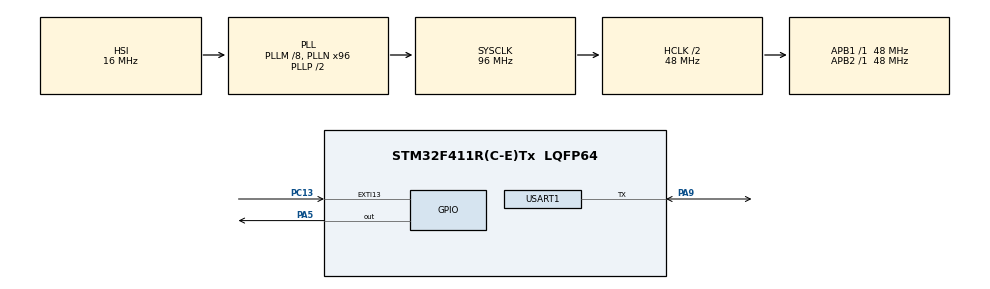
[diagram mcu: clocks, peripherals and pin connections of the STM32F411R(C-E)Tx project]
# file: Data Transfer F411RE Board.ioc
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Dma.Request0=USART1_RX
Dma.Request1=USART1_TX
Dma.USART1_RX.0.Direction=DMA_PERIPH_TO_MEMORY
Dma.USART1_RX.0.FIFOMode=DMA_FIFOMODE_DISABLE
Dma.USART1_RX.0.Instance=DMA2_Stream2
Dma.USART1_RX.0.MemDataAlignment=DMA_MDATAALIGN_BYTE
Dma.USART1_RX.0.MemInc=DMA_MINC_ENABLE
Dma.USART1_RX.0.Mode=DMA_NORMAL
Dma.USART1_RX.0.PeriphDataAlignment=DMA_PDATAALIGN_BYTE
Dma.USART1_RX.0.PeriphInc=DMA_PINC_DISABLE
Dma.USART1_RX.0.Priority=DMA_PRIORITY_LOW
Dma.USART1_TX.1.Direction=DMA_MEMORY_TO_PERIPH
Dma.USART1_TX.1.FIFOMode=DMA_FIFOMODE_DISABLE
Dma.USART1_TX.1.Instance=DMA2_Stream7
Dma.USART1_TX.1.MemDataAlignment=DMA_MDATAALIGN_BYTE
Dma.USART1_TX.1.MemInc=DMA_MINC_ENABLE
Dma.USART1_TX.1.Mode=DMA_NORMAL
Dma.USART1_TX.1.PeriphDataAlignment=DMA_PDATAALIGN_BYTE
Dma.USART1_TX.1.PeriphInc=DMA_PINC_DISABLE
Dma.USART1_TX.1.Priority=DMA_PRIORITY_LOW
Mcu.Family=STM32F4
Mcu.Name=STM32F411R(C-E)Tx
Mcu.Package=LQFP64
NVIC.DMA2_Stream2_IRQn=true\:0\:0\:false\:false\:true\:false\:true\:true
NVIC.DMA2_Stream7_IRQn=true\:0\:0\:false\:false\:true\:false\:true\:true
NVIC.EXTI15_10_IRQn=true\:0\:0\:false\:false\:true\:true\:true\:true
NVIC.PriorityGroup=NVIC_PRIORITYGROUP_0
NVIC.USART1_IRQn=true\:0\:0\:false\:false\:true\:true\:true\:true
PA13.GPIO_Label=TMS
PA13.Mode=Trace_Asynchronous_SW
PA13.Signal=SYS_JTMS-SWDIO
PA14.GPIO_Label=TCK
PA14.Mode=Trace_Asynchronous_SW
PA14.Signal=SYS_JTCK-SWCLK
PA2.GPIO_Label=USART_TX
PA2.Signal=USART2_TX
PA3.GPIO_Label=USART_RX
PA3.Signal=USART2_RX
PA5.Signal=GPIO_Output
PA9.GPIO_PuPd=GPIO_PULLUP
PA9.Mode=Half_duplex(single_wire_mode)
PA9.Signal=USART1_TX
PB3.GPIO_Label=SWO
PB3.Mode=Trace_Asynchronous_SW
PB3.Signal=SYS_JTDO-SWO
PC13-ANTI_TAMP.GPIO_PuPd=GPIO_PULLUP
PC13-ANTI_TAMP.Signal=GPXTI13
PC14-OSC32_IN.Mode=LSE-External-Oscillator
PC14-OSC32_IN.Signal=RCC_OSC32_IN
PC15-OSC32_OUT.Mode=LSE-External-Oscillator
PC15-OSC32_OUT.Signal=RCC_OSC32_OUT
PH0\ -\ OSC_IN.Mode=HSE-External-Clock-Source
PH0\ -\ OSC_IN.Signal=RCC_OSC_IN
PH1\ -\ OSC_OUT.Mode=HSE-External-Clock-Source
PH1\ -\ OSC_OUT.Signal=RCC_OSC_OUT
ProjectManager.HeapSize=0x200
ProjectManager.StackSize=0x400
ProjectManager.TargetToolchain=STM32CubeIDE
RCC.48MHZClocksFreq_Value=48000000
RCC.AHBCLKDivider=RCC_SYSCLK_DIV2
RCC.AHBFreq_Value=48000000
RCC.APB1Freq_Value=48000000
RCC.APB1TimFreq_Value=48000000
RCC.APB2Freq_Value=48000000
RCC.APB2TimFreq_Value=48000000
RCC.CortexFreq_Value=48000000
RCC.FLatency-AdvancedSettings=FLASH_LATENCY_1
RCC.HCLKFreq_Value=48000000
RCC.HSE_VALUE=8000000
RCC.HSI_VALUE=16000000
RCC.PLLM=8
RCC.PLLN=96
RCC.SYSCLKFreq_VALUE=96000000
RCC.SYSCLKSource=RCC_SYSCLKSOURCE_PLLCLK
RCC.VCOOutputFreq_Value=192000000
USART1.BaudRate=9600
USART1.VirtualMode=VM_ASYNC
board=NUCLEO-F411RE

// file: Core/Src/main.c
#include "main.h"
#include "stdio.h"

UART_HandleTypeDef huart1;
DMA_HandleTypeDef hdma_usart1_rx;
DMA_HandleTypeDef hdma_usart1_tx;

void SystemClock_Config(void);
static void MX_GPIO_Init(void);
static void MX_DMA_Init(void);
static void MX_USART1_UART_Init(void);
void DisplayValue(uint8_t value);

//bit0=A, bit1=B, bit2=C, bit3=D, bit4=E, bit5=F, bit6=G
const uint8_t SegmentMap[16] = {
	0b00111111, // 0
	0b00000110, // 1
	0b01011011, // 2
	0b01001111, // 3
	0b01100110, // 4
	0b01101101, // 5
	0b01111101, // 6
	0b00000111, // 7
	0b01111111, // 8
	0b01101111, // 9
	0b01110111, // A
	0b01111100, // B
	0b00111001, // C
	0b01011110, // D
	0b01111001, // E
	0b01110001  // F
};

typedef enum {
    STATE_IDLE,
    STATE_SEND_UART,
	STATE_PROCESS_RX
} SystemState_t;

SystemState_t currentState = STATE_IDLE;

uint8_t RxData[1];
uint8_t TxData[1];
uint8_t receivedValue = 0;
uint8_t rxFlag = 0;
uint8_t count = 0;
uint8_t isClicked = 0;

void HAL_UARTEx_RxEventCallback(UART_HandleTypeDef *huart, uint16_t Size)
{
	if (huart->Instance == USART1)
	{
		receivedValue = RxData[0];
		rxFlag = 1;

		HAL_UARTEx_ReceiveToIdle_IT(&huart1, RxData, 1);
	    }
}

void HAL_GPIO_EXTI_Callback(uint16_t GPIO_Pin)
{
	if (GPIO_Pin == GPIO_PIN_13)
	{
		isClicked = 1;
	}
}

int main(void)
{
  HAL_Init();
  SystemClock_Config();
  MX_GPIO_Init();
  MX_DMA_Init();
  MX_USART1_UART_Init();

  HAL_HalfDuplex_EnableReceiver(&huart1);
  HAL_UARTEx_ReceiveToIdle_IT(&huart1, RxData, 1);

  DisplayValue(count);

  while (1)
  {
  switch (currentState)
  {
	  case STATE_IDLE:
		  if (isClicked)
		  {
			  currentState = STATE_SEND_UART;
		  } else if (rxFlag)
		  {
			  currentState = STATE_PROCESS_RX;
		  }
		  break;

	  case STATE_SEND_UART:
	  {
		  HAL_Delay(100); // debounce
		  TxData[0] = count;

		  HAL_HalfDuplex_EnableTransmitter(&huart1);
		  HAL_UART_Transmit(&huart1, TxData, 1, 1000);
		  HAL_HalfDuplex_EnableReceiver(&huart1);

		  isClicked = 0;
		  currentState = STATE_IDLE;
		  break;
	  }

	  case STATE_PROCESS_RX:
	          {
	              count = receivedValue + 1;
	              if (count > 15)
	              {
	            	  count = 0;
	              }
	              DisplayValue(count);
	              rxFlag = 0;

	              currentState = STATE_IDLE;
	              break;
	          }

	  default:
		  currentState = STATE_IDLE;
		  break;
       }
   }
}

void DisplayValue(uint8_t value)
{
    uint8_t segments = SegmentMap[value];

    // PA0(A), PA1(B), PA4(E), PA5(F), PA6(G)
    HAL_GPIO_WritePin(GPIOA, GPIO_PIN_0, (segments & (1<<0)) ? GPIO_PIN_RESET : GPIO_PIN_SET);
    HAL_GPIO_WritePin(GPIOA, GPIO_PIN_1, (segments & (1<<1)) ? GPIO_PIN_RESET : GPIO_PIN_SET);
    HAL_GPIO_WritePin(GPIOA, GPIO_PIN_4, (segments & (1<<4)) ? GPIO_PIN_RESET : GPIO_PIN_SET);
    HAL_GPIO_WritePin(GPIOA, GPIO_PIN_5, (segments & (1<<5)) ? GPIO_PIN_RESET : GPIO_PIN_SET);
    HAL_GPIO_WritePin(GPIOA, GPIO_PIN_6, (segments & (1<<6)) ? GPIO_PIN_RESET : GPIO_PIN_SET);

    // PC10(C), PC11(D)
    HAL_GPIO_WritePin(GPIOC, GPIO_PIN_10, (segments & (1<<2)) ? GPIO_PIN_RESET : GPIO_PIN_SET);
    HAL_GPIO_WritePin(GPIOC, GPIO_PIN_11, (segments & (1<<3)) ? GPIO_PIN_RESET : GPIO_PIN_SET);
}

void SystemClock_Config(void)
{
  RCC_OscInitTypeDef RCC_OscInitStruct = {0};
  RCC_ClkInitTypeDef RCC_ClkInitStruct = {0};

  /** Configure the main internal regulator output voltage
  */
  __HAL_RCC_PWR_CLK_ENABLE();
  __HAL_PWR_VOLTAGESCALING_CONFIG(PWR_REGULATOR_VOLTAGE_SCALE1);

  /** Initializes the RCC Oscillators according to the specified parameters
  * in the RCC_OscInitTypeDef structure.
  */
  RCC_OscInitStruct.OscillatorType = RCC_OSCILLATORTYPE_HSI;
  RCC_OscInitStruct.HSIState = RCC_HSI_ON;
  RCC_OscInitStruct.HSICalibrationValue = RCC_HSICALIBRATION_DEFAULT;
  RCC_OscInitStruct.PLL.PLLState = RCC_PLL_ON;
  RCC_OscInitStruct.PLL.PLLSource = RCC_PLLSOURCE_HSI;
  RCC_OscInitStruct.PLL.PLLM = 8;
  RCC_OscInitStruct.PLL.PLLN = 96;
  RCC_OscInitStruct.PLL.PLLP = RCC_PLLP_DIV2;
  RCC_OscInitStruct.PLL.PLLQ = 4;
  if (HAL_RCC_OscConfig(&RCC_OscInitStruct) != HAL_OK)
  {
    Error_Handler();
  }

  /** Initializes the CPU, AHB and APB buses clocks
  */
  RCC_ClkInitStruct.ClockType = RCC_CLOCKTYPE_HCLK|RCC_CLOCKTYPE_SYSCLK
                              |RCC_CLOCKTYPE_PCLK1|RCC_CLOCKTYPE_PCLK2;
  RCC_ClkInitStruct.SYSCLKSource = RCC_SYSCLKSOURCE_PLLCLK;
  RCC_ClkInitStruct.AHBCLKDivider = RCC_SYSCLK_DIV2;
  RCC_ClkInitStruct.APB1CLKDivider = RCC_HCLK_DIV1;
  RCC_ClkInitStruct.APB2CLKDivider = RCC_HCLK_DIV1;

  if (HAL_RCC_ClockConfig(&RCC_ClkInitStruct, FLASH_LATENCY_1) != HAL_OK)
  {
    Error_Handler();
  }
}

static void MX_USART1_UART_Init(void)
{
  huart1.Instance = USART1;
  huart1.Init.BaudRate = 9600;
  huart1.Init.WordLength = UART_WORDLENGTH_8B;
  huart1.Init.StopBits = UART_STOPBITS_1;
  huart1.Init.Parity = UART_PARITY_NONE;
  huart1.Init.Mode = UART_MODE_TX_RX;
  huart1.Init.HwFlowCtl = UART_HWCONTROL_NONE;
  huart1.Init.OverSampling = UART_OVERSAMPLING_16;
  if (HAL_HalfDuplex_Init(&huart1) != HAL_OK)
  {
    Error_Handler();
  }
}

static void MX_DMA_Init(void)
{

  /* DMA controller clock enable */
  __HAL_RCC_DMA2_CLK_ENABLE();

  /* DMA interrupt init */
  /* DMA2_Stream2_IRQn interrupt configuration */
  HAL_NVIC_SetPriority(DMA2_Stream2_IRQn, 0, 0);
  HAL_NVIC_EnableIRQ(DMA2_Stream2_IRQn);
  /* DMA2_Stream7_IRQn interrupt configuration */
  HAL_NVIC_SetPriority(DMA2_Stream7_IRQn, 0, 0);
  HAL_NVIC_EnableIRQ(DMA2_Stream7_IRQn);

}

static void MX_GPIO_Init(void)
{
  GPIO_InitTypeDef GPIO_InitStruct = {0};
  __HAL_RCC_GPIOC_CLK_ENABLE();
  __HAL_RCC_GPIOH_CLK_ENABLE();
  __HAL_RCC_GPIOA_CLK_ENABLE();
  __HAL_RCC_GPIOB_CLK_ENABLE();

  /*Configure GPIO pin Output Level */
  HAL_GPIO_WritePin(GPIOA, GPIO_PIN_5, GPIO_PIN_RESET);

  /*Configure GPIO pin : PC13 */
  GPIO_InitStruct.Pin = GPIO_PIN_13;
  GPIO_InitStruct.Mode = GPIO_MODE_IT_RISING;
  GPIO_InitStruct.Pull = GPIO_PULLUP;
  HAL_GPIO_Init(GPIOC, &GPIO_InitStruct);

  /*Configure GPIO pins : USART_TX_Pin USART_RX_Pin */
  GPIO_InitStruct.Pin = USART_TX_Pin|USART_RX_Pin;
  GPIO_InitStruct.Mode = GPIO_MODE_AF_PP;
  GPIO_InitStruct.Pull = GPIO_NOPULL;
  GPIO_InitStruct.Speed = GPIO_SPEED_FREQ_VERY_HIGH;
  GPIO_InitStruct.Alternate = GPIO_AF7_USART2;
  HAL_GPIO_Init(GPIOA, &GPIO_InitStruct);

  /* Configure GPIOA: PA0, PA1, PA4, PA5, PA6 as output */
  GPIO_InitStruct.Pin = GPIO_PIN_0 | GPIO_PIN_1 | GPIO_PIN_4 | GPIO_PIN_5 | GPIO_PIN_6;
  GPIO_InitStruct.Mode = GPIO_MODE_OUTPUT_PP;
  GPIO_InitStruct.Pull = GPIO_NOPULL;
  GPIO_InitStruct.Speed = GPIO_SPEED_FREQ_LOW;
  HAL_GPIO_Init(GPIOA, &GPIO_InitStruct);

  /* Configure GPIOC: PC10, PC11 as output */
  GPIO_InitStruct.Pin = GPIO_PIN_10 | GPIO_PIN_11;
  HAL_GPIO_Init(GPIOC, &GPIO_InitStruct);

  /* EXTI interrupt init*/
  HAL_NVIC_SetPriority(EXTI15_10_IRQn, 0, 0);
  HAL_NVIC_EnableIRQ(EXTI15_10_IRQn);
}

void Error_Handler(void)
{
  __disable_irq();
  while (1)
  {
  }
}
